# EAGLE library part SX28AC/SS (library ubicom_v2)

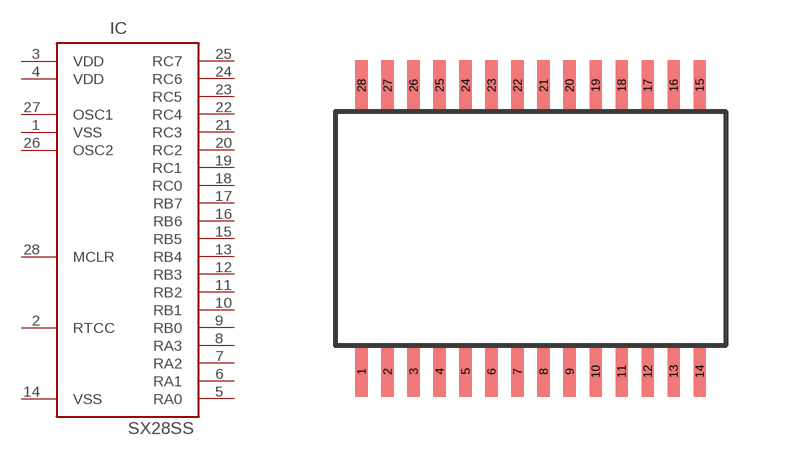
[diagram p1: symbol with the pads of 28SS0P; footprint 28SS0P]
Designator prefix IC

## SX28AC/SS  [28SS0P]
1  VSS  pwr
2  RTCC  in
3  VDD  pwr
4  VDD  pwr
5  RA0
6  RA1
7  RA2
8  RA3
9  RB0
10  RB1
11  RB2
12  RB3
13  RB4
14  VSS  pwr
15  RB5
16  RB6
17  RB7
18  RC0
19  RC1
20  RC2
21  RC3
22  RC4
23  RC5
24  RC6
25  RC7
26  OSC2  out
27  OSC1  in
28  MCLR  in

## Footprint 28SS0P (pad centres in mm)
smd 0.305 x 1.27: 1 -3.901,-3.576; 2 -3.251,-3.576; 3 -2.601,-3.576; 4 -1.951,-3.576; 5 -1.3,-3.576; 6 -0.65,-3.576; 7 0,-3.576; 8 0.65,-3.576; 9 1.3,-3.576; 10 1.951,-3.576; 11 2.601,-3.576; 12 3.251,-3.576; 13 3.901,-3.576; 14 4.552,-3.576; 15 4.552,3.576; 16 3.901,3.576; 17 3.251,3.576; 18 2.601,3.576; 19 1.951,3.576; 20 1.3,3.576; 21 0.65,3.576; 22 0,3.576; 23 -0.65,3.576; 24 -1.3,3.576; 25 -1.951,3.576; 26 -2.601,3.576; 27 -3.251,3.576; 28 -3.901,3.576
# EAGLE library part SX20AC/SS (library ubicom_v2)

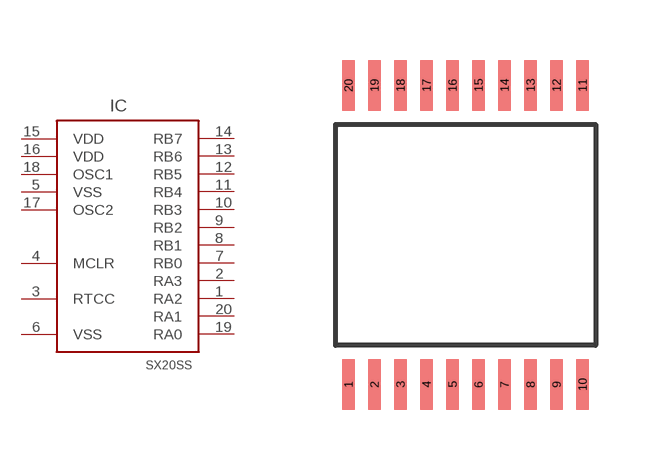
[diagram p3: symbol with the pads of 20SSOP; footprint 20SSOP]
Designator prefix IC

## SX20AC/SS  [20SSOP]
1  RA2
2  RA3
3  RTCC  in
4  MCLR  in
5  VSS  pwr
6  VSS  pwr
7  RB0
8  RB1
9  RB2
10  RB3
11  RB4
12  RB5
13  RB6
14  RB7
15  VDD  pwr
16  VDD  pwr
17  OSC2  out
18  OSC1  in
19  RA0
20  RA1

## Footprint 20SSOP (pad centres in mm)
smd 0.305 x 1.27: 1 -3.901,-3.901; 2 -3.251,-3.901; 3 -2.601,-3.901; 4 -1.951,-3.901; 5 -1.3,-3.901; 6 -0.65,-3.901; 7 0,-3.901; 8 0.65,-3.902; 9 1.3,-3.901; 10 1.951,-3.901; 11 1.951,3.576; 12 1.3,3.576; 13 0.65,3.576; 14 0,3.576; 15 -0.65,3.576; 16 -1.3,3.576; 17 -1.951,3.576; 18 -2.601,3.576; 19 -3.251,3.576; 20 -3.901,3.576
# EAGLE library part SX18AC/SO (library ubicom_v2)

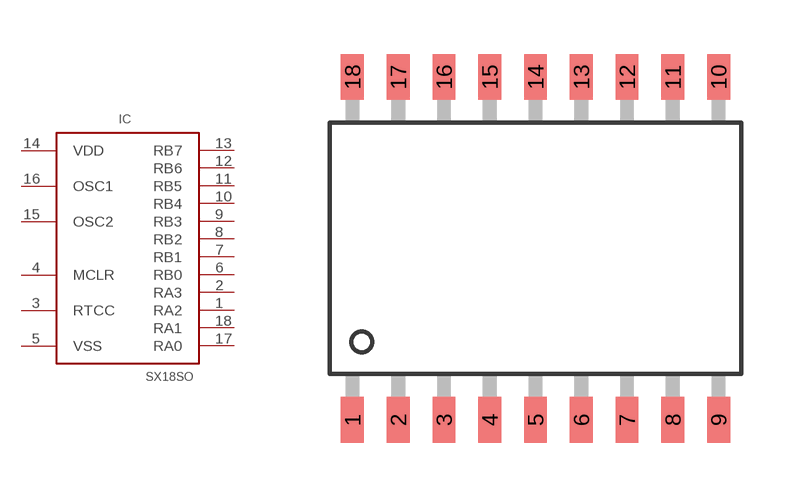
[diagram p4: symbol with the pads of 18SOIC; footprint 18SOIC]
Designator prefix IC

## SX18AC/SO  [18SOIC]
1  RA2
2  RA3
3  RTCC  in
4  MCLR  in
5  VSS  pwr
6  RB0
7  RB1
8  RB2
9  RB3
10  RB4
11  RB5
12  RB6
13  RB7
14  VDD  pwr
15  OSC2  out
16  OSC1  in
17  RA0
18  RA1

## Footprint 18SOIC (pad centres in mm)
smd 0.635 x 1.27: 1 -5.08,-5.08; 2 -3.81,-5.08; 3 -2.54,-5.08; 4 -1.27,-5.08; 5 0,-5.08; 6 1.27,-5.08; 7 2.54,-5.08; 8 3.81,-5.08; 9 5.08,-5.08; 10 5.08,4.445; 11 3.81,4.445; 12 2.54,4.445; 13 1.27,4.445; 14 0,4.445; 15 -1.27,4.445; 16 -2.54,4.445; 17 -3.81,4.445; 18 -5.08,4.445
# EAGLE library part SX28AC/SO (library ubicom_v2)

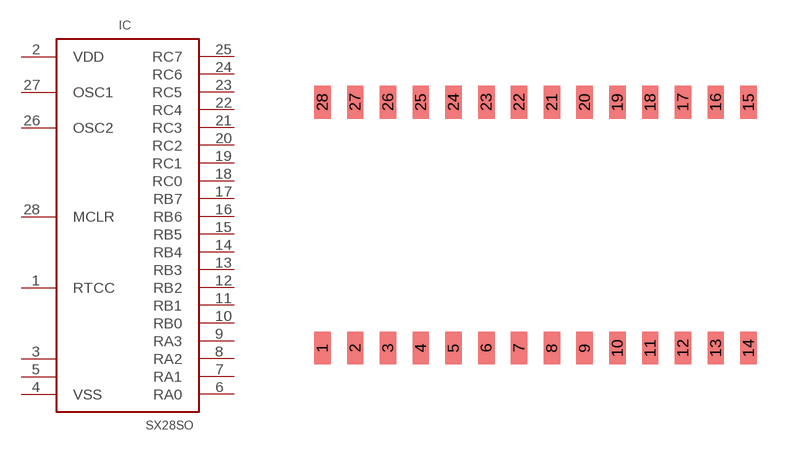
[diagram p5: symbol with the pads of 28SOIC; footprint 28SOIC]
Designator prefix IC

## SX28AC/SO  [28SOIC]
1  RTCC  in
2  VDD  pwr
3  NC  nc
4  VSS  pwr
5  NC  nc
6  RA0
7  RA1
8  RA2
9  RA3
10  RB0
11  RB1
12  RB2
13  RB3
14  RB4
15  RB5
16  RB6
17  RB7
18  RC0
19  RC1
20  RC2
21  RC3
22  RC4
23  RC5
24  RC6
25  RC7
26  OSC2  out
27  OSC1  in
28  MCLR  in

## Footprint 28SOIC (pad centres in mm)
smd 0.635 x 1.27: 1 -5.08,-5.08; 2 -3.81,-5.08; 3 -2.54,-5.08; 4 -1.27,-5.08; 5 0,-5.08; 6 1.27,-5.08; 7 2.54,-5.08; 8 3.81,-5.08; 9 5.08,-5.08; 10 6.35,-5.08; 11 7.62,-5.08; 12 8.89,-5.08; 13 10.16,-5.08; 14 11.43,-5.08; 15 11.43,4.445; 16 10.16,4.445; 17 8.89,4.445; 18 7.62,4.445; 19 6.35,4.445; 20 5.08,4.445; 21 3.81,4.445; 22 2.54,4.445; 23 1.27,4.445; 24 0,4.445; 25 -1.27,4.445; 26 -2.54,4.445; 27 -3.81,4.445; 28 -5.08,4.445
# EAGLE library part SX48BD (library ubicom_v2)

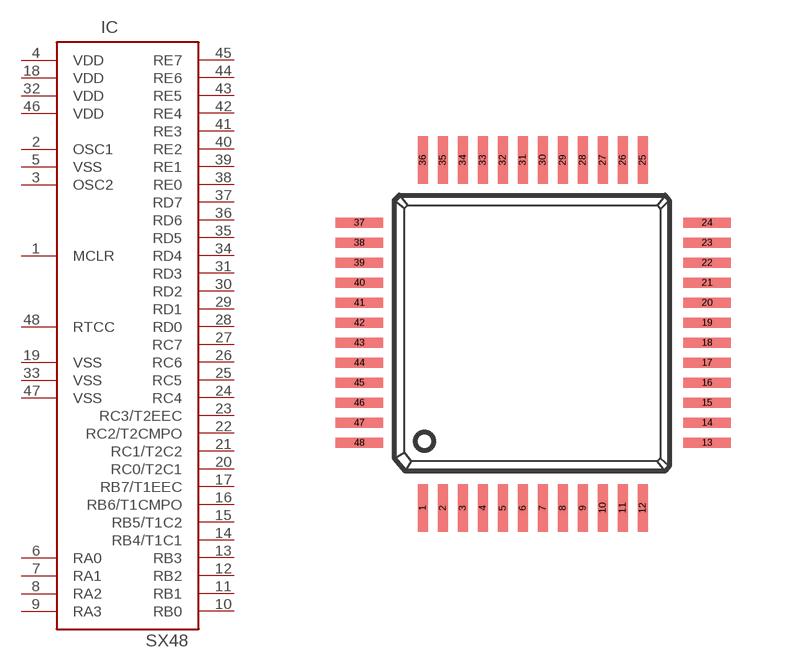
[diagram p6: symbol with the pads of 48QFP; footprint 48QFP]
Designator prefix IC

## SX48BD  [48QFP]
1  MCLR  in
2  OSC1  in
3  OSC2  out
4  VDD  pwr
5  VSS  pwr
6  RA0
7  RA1
8  RA2
9  RA3
10  RB0
11  RB1
12  RB2
13  RB3
14  RB4/T1C1
15  RB5/T1C2
16  RB6/T1CMPO
17  RB7/T1EEC
18  VDD  pwr
19  VSS  pwr
20  RC0/T2C1
21  RC1/T2C2
22  RC2/T2CMPO
23  RC3/T2EEC
24  RC4
25  RC5
26  RC6
27  RC7
28  RD0
29  RD1
30  RD2
31  RD3
32  VDD  pwr
33  VSS  pwr
34  RD4
35  RD5
36  RD6
37  RD7
38  RE0
39  RE1
40  RE2
41  RE3
42  RE4
43  RE5
44  RE6
45  RE7
46  VDD  pwr
47  VSS  pwr
48  RTCC  in

## Footprint 48QFP (pad centres in mm)
smd 0.25 x 1.2: 1 -2.74,-4.37; 2 -2.24,-4.37; 3 -1.74,-4.37; 4 -1.24,-4.37; 5 -0.74,-4.37; 6 -0.24,-4.37; 7 0.26,-4.37; 8 0.76,-4.37; 9 1.26,-4.37; 10 1.76,-4.37; 11 2.26,-4.37; 12 2.76,-4.37; 25 2.76,4.33; 26 2.26,4.33; 27 1.76,4.33; 28 1.26,4.33; 29 0.76,4.33; 30 0.26,4.33; 31 -0.24,4.33; 32 -0.74,4.33; 33 -1.24,4.33; 34 -1.74,4.33; 35 -2.24,4.33; 36 -2.74,4.33
smd 1.2 x 0.25: 13 4.37,-2.74; 14 4.37,-2.24; 15 4.37,-1.74; 16 4.37,-1.24; 17 4.37,-0.74; 18 4.37,-0.24; 19 4.37,0.26; 20 4.37,0.76; 21 4.37,1.26; 22 4.37,1.76; 23 4.37,2.26; 24 4.37,2.76; 37 -4.33,2.76; 38 -4.33,2.26; 39 -4.33,1.76; 40 -4.33,1.26; 41 -4.33,0.76; 42 -4.33,0.26; 43 -4.33,-0.24; 44 -4.33,-0.74; 45 -4.33,-1.24; 46 -4.33,-1.74; 47 -4.33,-2.24; 48 -4.33,-2.74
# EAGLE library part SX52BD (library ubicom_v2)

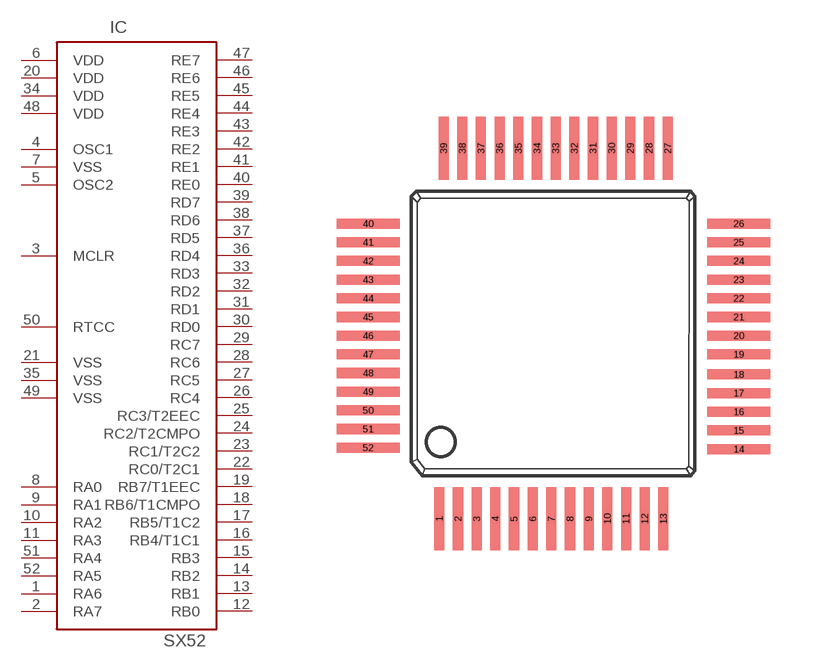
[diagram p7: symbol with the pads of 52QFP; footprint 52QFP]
Designator prefix IC

## SX52BD  [52QFP]
1  RA6
2  RA7
3  MCLR  in
4  OSC1  in
5  OSC2  out
6  VDD  pwr
7  VSS  pwr
8  RA0
9  RA1
10  RA2
11  RA3
12  RB0
13  RB1
14  RB2
15  RB3
16  RB4/T1C1
17  RB5/T1C2
18  RB6/T1CMPO
19  RB7/T1EEC
20  VDD  pwr
21  VSS  pwr
22  RC0/T2C1
23  RC1/T2C2
24  RC2/T2CMPO
25  RC3/T2EEC
26  RC4
27  RC5
28  RC6
29  RC7
30  RD0
31  RD1
32  RD2
33  RD3
34  VDD  pwr
35  VSS  pwr
36  RD4
37  RD5
38  RD6
39  RD7
40  RE0
41  RE1
42  RE2
43  RE3
44  RE4
45  RE5
46  RE6
47  RE7
48  VDD  pwr
49  VSS  pwr
50  RTCC  in
51  RA4
52  RA5

## Footprint 52QFP (pad centres in mm)
smd 0.35 x 2.2: 1 -3.975,-6.45; 2 -3.325,-6.45; 3 -2.675,-6.45; 4 -2.025,-6.45; 5 -1.375,-6.45; 6 -0.725,-6.45; 7 -0.075,-6.45; 8 0.575,-6.45; 9 1.225,-6.45; 10 1.875,-6.45; 11 2.525,-6.45; 12 3.175,-6.45; 13 3.825,-6.45; 27 3.975,6.45; 28 3.325,6.45; 29 2.675,6.45; 30 2.025,6.45; 31 1.375,6.45; 32 0.725,6.45; 33 0.075,6.45; 34 -0.575,6.45; 35 -1.225,6.45; 36 -1.875,6.45; 37 -2.525,6.45; 38 -3.175,6.45; 39 -3.825,6.45
smd 2.2 x 0.35: 14 6.45,-4.025; 15 6.45,-3.375; 16 6.45,-2.725; 17 6.45,-2.075; 18 6.45,-1.425; 19 6.45,-0.725; 20 6.45,-0.075; 21 6.45,0.575; 22 6.45,1.225; 23 6.45,1.875; 24 6.45,2.525; 25 6.45,3.175; 26 6.45,3.825; 40 -6.45,3.825; 41 -6.45,3.175; 42 -6.45,2.525; 43 -6.45,1.875; 44 -6.45,1.225; 45 -6.45,0.575; 46 -6.45,-0.075; 47 -6.45,-0.725; 48 -6.45,-1.375; 49 -6.45,-2.025; 50 -6.45,-2.675; 51 -6.45,-3.325; 52 -6.45,-3.975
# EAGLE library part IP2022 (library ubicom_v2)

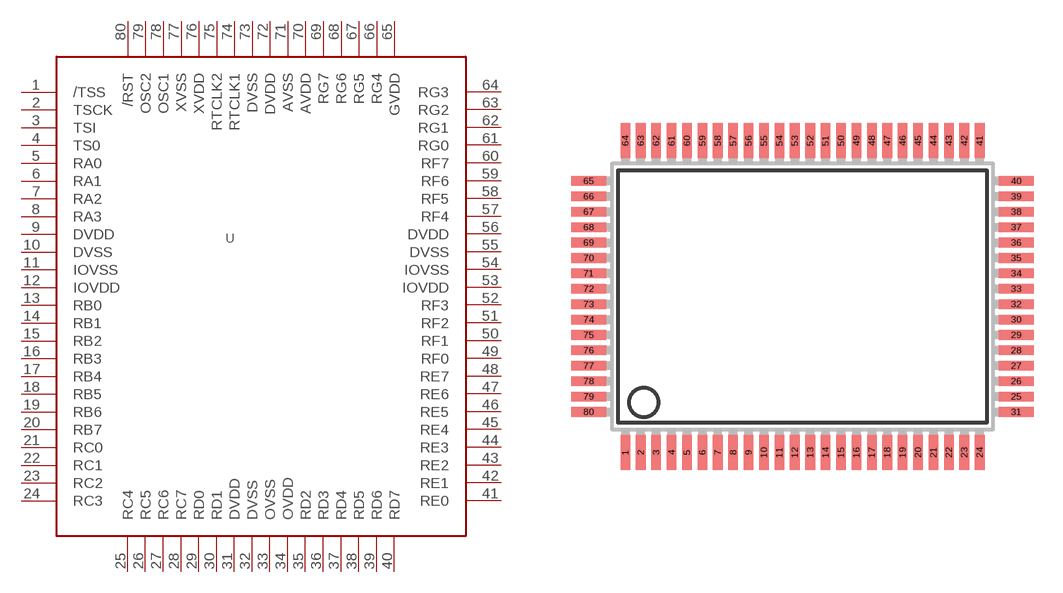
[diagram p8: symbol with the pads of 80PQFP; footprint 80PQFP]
Designator prefix -

## IP2022PQFP  [80PQFP]
1  /TSS  in
2  TSCK  in
3  TSI  in
4  TS0  out
5  RA0
6  RA1
7  RA2
8  RA3
9  DVDD  pwr
10  DVSS  pwr
11  IOVSS  pwr
12  IOVDD  pwr
13  RB0
14  RB1
15  RB2
16  RB3
17  RB4
18  RB5
19  RB6
20  RB7
21  RC0
22  RC1
23  RC2
24  RC3
25  RC4
26  RC5
27  RC6
28  RC7
29  RD0
30  RD1
31  DVDD  pwr
32  DVSS  pwr
33  OVSS  pwr
34  OVDD  pwr
35  RD2
36  RD3
37  RD4
38  RD5
39  RD6
40  RD7
41  RE0
42  RE1
43  RE2
44  RE3
45  RE4
46  RE5
47  RE6
48  RE7
49  RF0
50  RF1
51  RF2
52  RF3
53  IOVDD  pwr
54  IOVSS  pwr
55  DVSS  pwr
56  DVDD  pwr
57  RF4
58  RF5
59  RF6
60  RF7
61  RG0
62  RG1
63  RG2
64  RG3
65  GVDD  pwr
66  RG4
67  RG5
68  RG6
69  RG7
70  AVDD  pwr
71  AVSS  pwr
72  DVDD  pwr
73  DVSS  pwr
74  RTCLK1  in
75  RTCLK2  out
76  XVDD  pwr
77  XVSS  pwr
78  OSC1  in
79  OSC2  out
80  /RST

## Footprint 80PQFP (pad centres in mm)
smd 0.5 x 1.8: 1 -9.2,-8.1; 2 -8.4,-8.1; 3 -7.6,-8.1; 4 -6.8,-8.1; 5 -6,-8.1; 6 -5.2,-8.1; 7 -4.4,-8.1; 8 -3.6,-8.1; 9 -2.8,-8.1; 10 -2,-8.1; 11 -1.2,-8.1; 12 -0.4,-8.1; 13 0.4,-8.1; 14 1.2,-8.1; 15 2,-8.1; 16 2.8,-8.1; 17 3.6,-8.1; 18 4.4,-8.1; 19 5.2,-8.1; 20 6,-8.1; 21 6.8,-8.1; 22 7.6,-8.1; 23 8.4,-8.1; 24 9.2,-8.1; 41 9.2,8.1; 42 8.4,8.1; 43 7.6,8.1; 44 6.8,8.1; 45 6,8.1; 46 5.2,8.1; 47 4.4,8.1; 48 3.6,8.1; 49 2.8,8.1; 50 2,8.1; 51 1.2,8.1; 52 0.4,8.1; 53 -0.4,8.1; 54 -1.2,8.1; 55 -2,8.1; 56 -2.8,8.1; 57 -3.6,8.1; 58 -4.4,8.1; 59 -5.2,8.1; 60 -6,8.1; 61 -6.8,8.1; 62 -7.6,8.1; 63 -8.4,8.1; 64 -9.2,8.1
smd 1.8 x 0.5: 25 11.1,-5.2; 26 11.1,-4.4; 27 11.1,-3.6; 28 11.1,-2.8; 29 11.1,-2; 30 11.1,-1.2; 31 11.1,-6; 32 11.1,-0.4; 33 11.1,0.4; 34 11.1,1.2; 35 11.1,2; 36 11.1,2.8; 37 11.1,3.6; 38 11.1,4.4; 39 11.1,5.2; 40 11.1,6; 65 -11.1,6; 66 -11.1,5.2; 67 -11.1,4.4; 68 -11.1,3.6; 69 -11.1,2.8; 70 -11.1,2; 71 -11.1,1.2; 72 -11.1,0.4; 73 -11.1,-0.4; 74 -11.1,-1.2; 75 -11.1,-2; 76 -11.1,-2.8; 77 -11.1,-3.6; 78 -11.1,-4.4; 79 -11.1,-5.2; 80 -11.1,-6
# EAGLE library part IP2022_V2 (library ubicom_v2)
Ubicom IP2022 Internet Processor

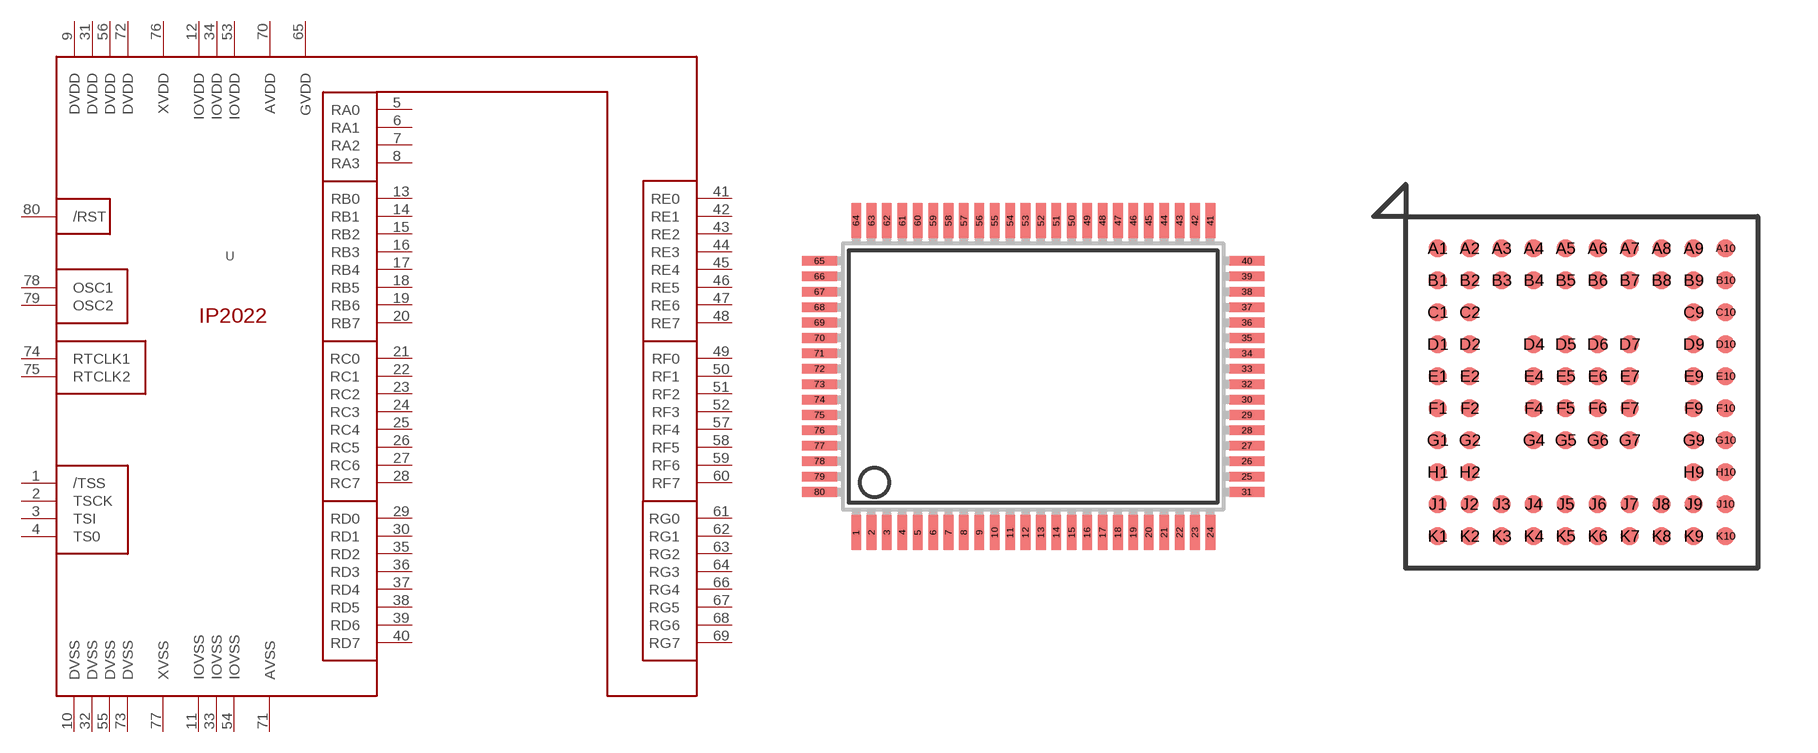
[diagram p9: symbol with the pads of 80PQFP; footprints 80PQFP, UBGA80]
Designator prefix U

## IP2022_V2PQFP  [80PQFP]
1  /TSS  in
2  TSCK  in
3  TSI  in
4  TS0  out
5  RA0
6  RA1
7  RA2
8  RA3
9  DVDD  pwr
10  DVSS  pwr
11  IOVSS  pwr
12  IOVDD  pwr
13  RB0
14  RB1
15  RB2
16  RB3
17  RB4
18  RB5
19  RB6
20  RB7
21  RC0
22  RC1
23  RC2
24  RC3
25  RC4
26  RC5
27  RC6
28  RC7
29  RD0
30  RD1
31  DVDD  pwr
32  DVSS  pwr
33  IOVSS  pwr
34  IOVDD  pwr
35  RD2
36  RD3
37  RD4
38  RD5
39  RD6
40  RD7
41  RE0
42  RE1
43  RE2
44  RE3
45  RE4
46  RE5
47  RE6
48  RE7
49  RF0
50  RF1
51  RF2
52  RF3
53  IOVDD  pwr
54  IOVSS  pwr
55  DVSS  pwr
56  DVDD  pwr
57  RF4
58  RF5
59  RF6
60  RF7
61  RG0
62  RG1
63  RG2
64  RG3
65  GVDD  pwr
66  RG4
67  RG5
68  RG6
69  RG7
70  AVDD  pwr
71  AVSS  pwr
72  DVDD  pwr
73  DVSS  pwr
74  RTCLK1  in
75  RTCLK2  out
76  XVDD  pwr
77  XVSS  pwr
78  OSC1  in
79  OSC2  out
80  /RST  in

## IP2022_V2UBGA  [UBGA80]
A1  /TSS  in
A2  /RST  in
A3  OSC2  out
A4  XVDD  pwr
A5  RTCLK1  in
A6  AVSS  pwr
A7  RG6
A8  GVDD  pwr
A9  RF5
A10  RG3
B1  TSI  in
B2  TS0  out
B3  RA2
B4  OSC1  in
B5  RTCLK2  out
B6  AVDD  pwr
B7  RG4
B8  RG5
B9  RF4
B10  RG2
C1  RA1
C2  TSCK  in
C9  RG1
C10  RG0
D1  DVDD  pwr
D2  RA0
D4  XVSS  pwr
D5  DVSS  pwr
D6  DVDD  pwr
D7  RG7
D9  RF7
D10  RF6
E1  DVSS  pwr
E2  IOVSS  pwr
E4  RA3
E5  IOVDD  pwr
E6  IOVDD  pwr
E7  IOVSS  pwr
E9  DVDD  pwr
E10  DVSS  pwr
F1  RB1
F2  RB2
F4  RB4
F5  RB0
F6  RF3
F7  RF0
F9  RF1
F10  RF2
G1  RB3
G2  RB6
G4  RD0
G5  DVDD  pwr
G6  IOVDD  pwr
G7  RD3
G9  RE5
G10  RE6
H1  RB7
H2  RC1
H9  RE1
H10  RE4
J1  RC2
J2  RC0
J3  RB5
J4  RC6
J5  RD1
J6  RD2
J7  RD5
J8  RE7
J9  RE3
J10  RE2
K1  RC3
K2  RC4
K3  RC5
K4  RC7
K5  DVSS  pwr
K6  IOVSS  pwr
K7  RD4
K8  RD6
K9  RD7
K10  RE0

## Footprint 80PQFP (pad centres in mm)
smd 0.5 x 1.8: 1 -9.2,-8.1; 2 -8.4,-8.1; 3 -7.6,-8.1; 4 -6.8,-8.1; 5 -6,-8.1; 6 -5.2,-8.1; 7 -4.4,-8.1; 8 -3.6,-8.1; 9 -2.8,-8.1; 10 -2,-8.1; 11 -1.2,-8.1; 12 -0.4,-8.1; 13 0.4,-8.1; 14 1.2,-8.1; 15 2,-8.1; 16 2.8,-8.1; 17 3.6,-8.1; 18 4.4,-8.1; 19 5.2,-8.1; 20 6,-8.1; 21 6.8,-8.1; 22 7.6,-8.1; 23 8.4,-8.1; 24 9.2,-8.1; 41 9.2,8.1; 42 8.4,8.1; 43 7.6,8.1; 44 6.8,8.1; 45 6,8.1; 46 5.2,8.1; 47 4.4,8.1; 48 3.6,8.1; 49 2.8,8.1; 50 2,8.1; 51 1.2,8.1; 52 0.4,8.1; 53 -0.4,8.1; 54 -1.2,8.1; 55 -2,8.1; 56 -2.8,8.1; 57 -3.6,8.1; 58 -4.4,8.1; 59 -5.2,8.1; 60 -6,8.1; 61 -6.8,8.1; 62 -7.6,8.1; 63 -8.4,8.1; 64 -9.2,8.1
smd 1.8 x 0.5: 25 11.1,-5.2; 26 11.1,-4.4; 27 11.1,-3.6; 28 11.1,-2.8; 29 11.1,-2; 30 11.1,-1.2; 31 11.1,-6; 32 11.1,-0.4; 33 11.1,0.4; 34 11.1,1.2; 35 11.1,2; 36 11.1,2.8; 37 11.1,3.6; 38 11.1,4.4; 39 11.1,5.2; 40 11.1,6; 65 -11.1,6; 66 -11.1,5.2; 67 -11.1,4.4; 68 -11.1,3.6; 69 -11.1,2.8; 70 -11.1,2; 71 -11.1,1.2; 72 -11.1,0.4; 73 -11.1,-0.4; 74 -11.1,-1.2; 75 -11.1,-2; 76 -11.1,-2.8; 77 -11.1,-3.6; 78 -11.1,-4.4; 79 -11.1,-5.2; 80 -11.1,-6

## Footprint UBGA80 (pad centres in mm)
uBGA 80pin
smd 0.44 x 0.44: A1 0,0; A2 0.8,0; A3 1.6,0; A4 2.4,0; A5 3.2,0; A6 4,0; A7 4.8,0; A8 5.6,0; A9 6.4,0; A10 7.2,0; B1 0,-0.8; B2 0.8,-0.8; B3 1.6,-0.8; B4 2.4,-0.8; B5 3.2,-0.8; B6 4,-0.8; B7 4.8,-0.8; B8 5.6,-0.8; B9 6.4,-0.8; B10 7.2,-0.8; C1 0,-1.6; C2 0.8,-1.6; C9 6.4,-1.6; C10 7.2,-1.6; D1 0,-2.4; D2 0.8,-2.4; D4 2.4,-2.4; D5 3.2,-2.4; D6 4,-2.4; D7 4.8,-2.4; D9 6.4,-2.4; D10 7.2,-2.4; E1 0,-3.2; E2 0.8,-3.2; E4 2.4,-3.2; E5 3.2,-3.2; E6 4,-3.2; E7 4.8,-3.2; E9 6.4,-3.2; E10 7.2,-3.2; F1 0,-4; F2 0.8,-4; F4 2.4,-4; F5 3.2,-4; F6 4,-4; F7 4.8,-4; F9 6.4,-4; F10 7.2,-4; G1 0,-4.8; G2 0.8,-4.8; G4 2.4,-4.8; G5 3.2,-4.8; G6 4,-4.8; G7 4.8,-4.8; G9 6.4,-4.8; G10 7.2,-4.8; H1 0,-5.6; H2 0.8,-5.6; H9 6.4,-5.6; H10 7.2,-5.6; J1 0,-6.4; J2 0.8,-6.4; J3 1.6,-6.4; J4 2.4,-6.4; J5 3.2,-6.4; J6 4,-6.4; J7 4.8,-6.4; J8 5.6,-6.4; J9 6.4,-6.4; J10 7.2,-6.4; K1 0,-7.2; K2 0.8,-7.2; K3 1.6,-7.2; K4 2.4,-7.2; K5 3.2,-7.2; K6 4,-7.2; K7 4.8,-7.2; K8 5.6,-7.2; K9 6.4,-7.2; K10 7.2,-7.2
